VERSION 5.4 ;
NAMESCASESENSITIVE ON ;
BUSBITCHARS "[]" ;
DIVIDERCHAR "/" ;
UNITS
  DATABASE MICRONS 2000 ;
END UNITS
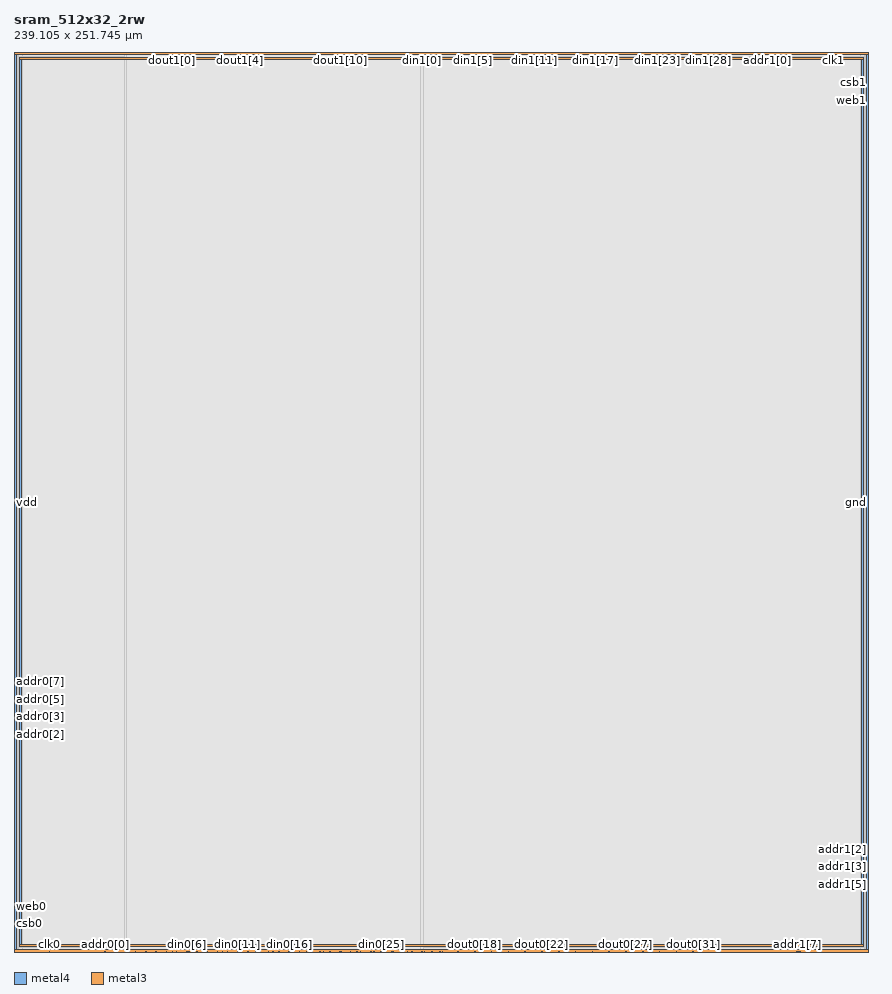
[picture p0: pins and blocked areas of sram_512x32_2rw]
MACRO sram_512x32_2rw
   CLASS BLOCK ;
   SIZE 239.105 BY 251.745 ;
   SYMMETRY X Y R90 ;
   PIN din0[0]
      DIRECTION INPUT ;
      PORT
         LAYER metal4 ;
         RECT  31.1175 0.0 31.2575 0.14 ;
      END
   END din0[0]
   PIN din0[1]
      DIRECTION INPUT ;
      PORT
         LAYER metal4 ;
         RECT  33.9775 0.0 34.1175 0.14 ;
      END
   END din0[1]
   PIN din0[2]
      DIRECTION INPUT ;
      PORT
         LAYER metal4 ;
         RECT  36.8375 0.0 36.9775 0.14 ;
      END
   END din0[2]
   PIN din0[3]
      DIRECTION INPUT ;
      PORT
         LAYER metal4 ;
         RECT  39.6975 0.0 39.8375 0.14 ;
      END
   END din0[3]
   PIN din0[4]
      DIRECTION INPUT ;
      PORT
         LAYER metal4 ;
         RECT  42.5575 0.0 42.6975 0.14 ;
      END
   END din0[4]
   PIN din0[5]
      DIRECTION INPUT ;
      PORT
         LAYER metal4 ;
         RECT  45.4175 0.0 45.5575 0.14 ;
      END
   END din0[5]
   PIN din0[6]
      DIRECTION INPUT ;
      PORT
         LAYER metal4 ;
         RECT  48.2775 0.0 48.4175 0.14 ;
      END
   END din0[6]
   PIN din0[7]
      DIRECTION INPUT ;
      PORT
         LAYER metal4 ;
         RECT  51.1375 0.0 51.2775 0.14 ;
      END
   END din0[7]
   PIN din0[8]
      DIRECTION INPUT ;
      PORT
         LAYER metal4 ;
         RECT  53.9975 0.0 54.1375 0.14 ;
      END
   END din0[8]
   PIN din0[9]
      DIRECTION INPUT ;
      PORT
         LAYER metal4 ;
         RECT  56.8575 0.0 56.9975 0.14 ;
      END
   END din0[9]
   PIN din0[10]
      DIRECTION INPUT ;
      PORT
         LAYER metal4 ;
         RECT  59.7175 0.0 59.8575 0.14 ;
      END
   END din0[10]
   PIN din0[11]
      DIRECTION INPUT ;
      PORT
         LAYER metal4 ;
         RECT  62.5775 0.0 62.7175 0.14 ;
      END
   END din0[11]
   PIN din0[12]
      DIRECTION INPUT ;
      PORT
         LAYER metal4 ;
         RECT  65.4375 0.0 65.5775 0.14 ;
      END
   END din0[12]
   PIN din0[13]
      DIRECTION INPUT ;
      PORT
         LAYER metal4 ;
         RECT  68.2975 0.0 68.4375 0.14 ;
      END
   END din0[13]
   PIN din0[14]
      DIRECTION INPUT ;
      PORT
         LAYER metal4 ;
         RECT  71.1575 0.0 71.2975 0.14 ;
      END
   END din0[14]
   PIN din0[15]
      DIRECTION INPUT ;
      PORT
         LAYER metal4 ;
         RECT  74.0175 0.0 74.1575 0.14 ;
      END
   END din0[15]
   PIN din0[16]
      DIRECTION INPUT ;
      PORT
         LAYER metal4 ;
         RECT  76.8775 0.0 77.0175 0.14 ;
      END
   END din0[16]
   PIN din0[17]
      DIRECTION INPUT ;
      PORT
         LAYER metal4 ;
         RECT  79.7375 0.0 79.8775 0.14 ;
      END
   END din0[17]
   PIN din0[18]
      DIRECTION INPUT ;
      PORT
         LAYER metal4 ;
         RECT  82.5975 0.0 82.7375 0.14 ;
      END
   END din0[18]
   PIN din0[19]
      DIRECTION INPUT ;
      PORT
         LAYER metal4 ;
         RECT  85.4575 0.0 85.5975 0.14 ;
      END
   END din0[19]
   PIN din0[20]
      DIRECTION INPUT ;
      PORT
         LAYER metal4 ;
         RECT  88.3175 0.0 88.4575 0.14 ;
      END
   END din0[20]
   PIN din0[21]
      DIRECTION INPUT ;
      PORT
         LAYER metal4 ;
         RECT  91.1775 0.0 91.3175 0.14 ;
      END
   END din0[21]
   PIN din0[22]
      DIRECTION INPUT ;
      PORT
         LAYER metal4 ;
         RECT  94.0375 0.0 94.1775 0.14 ;
      END
   END din0[22]
   PIN din0[23]
      DIRECTION INPUT ;
      PORT
         LAYER metal4 ;
         RECT  96.8975 0.0 97.0375 0.14 ;
      END
   END din0[23]
   PIN din0[24]
      DIRECTION INPUT ;
      PORT
         LAYER metal4 ;
         RECT  99.7575 0.0 99.8975 0.14 ;
      END
   END din0[24]
   PIN din0[25]
      DIRECTION INPUT ;
      PORT
         LAYER metal4 ;
         RECT  102.6175 0.0 102.7575 0.14 ;
      END
   END din0[25]
   PIN din0[26]
      DIRECTION INPUT ;
      PORT
         LAYER metal4 ;
         RECT  105.4775 0.0 105.6175 0.14 ;
      END
   END din0[26]
   PIN din0[27]
      DIRECTION INPUT ;
      PORT
         LAYER metal4 ;
         RECT  108.3375 0.0 108.4775 0.14 ;
      END
   END din0[27]
   PIN din0[28]
      DIRECTION INPUT ;
      PORT
         LAYER metal4 ;
         RECT  111.1975 0.0 111.3375 0.14 ;
      END
   END din0[28]
   PIN din0[29]
      DIRECTION INPUT ;
      PORT
         LAYER metal4 ;
         RECT  114.0575 0.0 114.1975 0.14 ;
      END
   END din0[29]
   PIN din0[30]
      DIRECTION INPUT ;
      PORT
         LAYER metal4 ;
         RECT  116.9175 0.0 117.0575 0.14 ;
      END
   END din0[30]
   PIN din0[31]
      DIRECTION INPUT ;
      PORT
         LAYER metal4 ;
         RECT  119.7775 0.0 119.9175 0.14 ;
      END
   END din0[31]
   PIN din1[0]
      DIRECTION INPUT ;
      PORT
         LAYER metal4 ;
         RECT  114.0325 251.605 114.1725 251.745 ;
      END
   END din1[0]
   PIN din1[1]
      DIRECTION INPUT ;
      PORT
         LAYER metal4 ;
         RECT  116.8925 251.605 117.0325 251.745 ;
      END
   END din1[1]
   PIN din1[2]
      DIRECTION INPUT ;
      PORT
         LAYER metal4 ;
         RECT  119.7525 251.605 119.8925 251.745 ;
      END
   END din1[2]
   PIN din1[3]
      DIRECTION INPUT ;
      PORT
         LAYER metal4 ;
         RECT  122.6125 251.605 122.7525 251.745 ;
      END
   END din1[3]
   PIN din1[4]
      DIRECTION INPUT ;
      PORT
         LAYER metal4 ;
         RECT  125.4725 251.605 125.6125 251.745 ;
      END
   END din1[4]
   PIN din1[5]
      DIRECTION INPUT ;
      PORT
         LAYER metal4 ;
         RECT  128.3325 251.605 128.4725 251.745 ;
      END
   END din1[5]
   PIN din1[6]
      DIRECTION INPUT ;
      PORT
         LAYER metal4 ;
         RECT  131.1925 251.605 131.3325 251.745 ;
      END
   END din1[6]
   PIN din1[7]
      DIRECTION INPUT ;
      PORT
         LAYER metal4 ;
         RECT  134.0525 251.605 134.1925 251.745 ;
      END
   END din1[7]
   PIN din1[8]
      DIRECTION INPUT ;
      PORT
         LAYER metal4 ;
         RECT  136.9125 251.605 137.0525 251.745 ;
      END
   END din1[8]
   PIN din1[9]
      DIRECTION INPUT ;
      PORT
         LAYER metal4 ;
         RECT  139.7725 251.605 139.9125 251.745 ;
      END
   END din1[9]
   PIN din1[10]
      DIRECTION INPUT ;
      PORT
         LAYER metal4 ;
         RECT  142.6325 251.605 142.7725 251.745 ;
      END
   END din1[10]
   PIN din1[11]
      DIRECTION INPUT ;
      PORT
         LAYER metal4 ;
         RECT  145.4925 251.605 145.6325 251.745 ;
      END
   END din1[11]
   PIN din1[12]
      DIRECTION INPUT ;
      PORT
         LAYER metal4 ;
         RECT  148.3525 251.605 148.4925 251.745 ;
      END
   END din1[12]
   PIN din1[13]
      DIRECTION INPUT ;
      PORT
         LAYER metal4 ;
         RECT  151.2125 251.605 151.3525 251.745 ;
      END
   END din1[13]
   PIN din1[14]
      DIRECTION INPUT ;
      PORT
         LAYER metal4 ;
         RECT  154.0725 251.605 154.2125 251.745 ;
      END
   END din1[14]
   PIN din1[15]
      DIRECTION INPUT ;
      PORT
         LAYER metal4 ;
         RECT  156.9325 251.605 157.0725 251.745 ;
      END
   END din1[15]
   PIN din1[16]
      DIRECTION INPUT ;
      PORT
         LAYER metal4 ;
         RECT  159.7925 251.605 159.9325 251.745 ;
      END
   END din1[16]
   PIN din1[17]
      DIRECTION INPUT ;
      PORT
         LAYER metal4 ;
         RECT  162.6525 251.605 162.7925 251.745 ;
      END
   END din1[17]
   PIN din1[18]
      DIRECTION INPUT ;
      PORT
         LAYER metal4 ;
         RECT  165.5125 251.605 165.6525 251.745 ;
      END
   END din1[18]
   PIN din1[19]
      DIRECTION INPUT ;
      PORT
         LAYER metal4 ;
         RECT  168.3725 251.605 168.5125 251.745 ;
      END
   END din1[19]
   PIN din1[20]
      DIRECTION INPUT ;
      PORT
         LAYER metal4 ;
         RECT  171.2325 251.605 171.3725 251.745 ;
      END
   END din1[20]
   PIN din1[21]
      DIRECTION INPUT ;
      PORT
         LAYER metal4 ;
         RECT  174.0925 251.605 174.2325 251.745 ;
      END
   END din1[21]
   PIN din1[22]
      DIRECTION INPUT ;
      PORT
         LAYER metal4 ;
         RECT  176.9525 251.605 177.0925 251.745 ;
      END
   END din1[22]
   PIN din1[23]
      DIRECTION INPUT ;
      PORT
         LAYER metal4 ;
         RECT  179.8125 251.605 179.9525 251.745 ;
      END
   END din1[23]
   PIN din1[24]
      DIRECTION INPUT ;
      PORT
         LAYER metal4 ;
         RECT  182.6725 251.605 182.8125 251.745 ;
      END
   END din1[24]
   PIN din1[25]
      DIRECTION INPUT ;
      PORT
         LAYER metal4 ;
         RECT  185.5325 251.605 185.6725 251.745 ;
      END
   END din1[25]
   PIN din1[26]
      DIRECTION INPUT ;
      PORT
         LAYER metal4 ;
         RECT  188.3925 251.605 188.5325 251.745 ;
      END
   END din1[26]
   PIN din1[27]
      DIRECTION INPUT ;
      PORT
         LAYER metal4 ;
         RECT  191.2525 251.605 191.3925 251.745 ;
      END
   END din1[27]
   PIN din1[28]
      DIRECTION INPUT ;
      PORT
         LAYER metal4 ;
         RECT  194.1125 251.605 194.2525 251.745 ;
      END
   END din1[28]
   PIN din1[29]
      DIRECTION INPUT ;
      PORT
         LAYER metal4 ;
         RECT  196.9725 251.605 197.1125 251.745 ;
      END
   END din1[29]
   PIN din1[30]
      DIRECTION INPUT ;
      PORT
         LAYER metal4 ;
         RECT  199.8325 251.605 199.9725 251.745 ;
      END
   END din1[30]
   PIN din1[31]
      DIRECTION INPUT ;
      PORT
         LAYER metal4 ;
         RECT  202.6925 251.605 202.8325 251.745 ;
      END
   END din1[31]
   PIN addr0[0]
      DIRECTION INPUT ;
      PORT
         LAYER metal4 ;
         RECT  25.3975 0.0 25.5375 0.14 ;
      END
   END addr0[0]
   PIN addr0[1]
      DIRECTION INPUT ;
      PORT
         LAYER metal4 ;
         RECT  28.2575 0.0 28.3975 0.14 ;
      END
   END addr0[1]
   PIN addr0[2]
      DIRECTION INPUT ;
      PORT
         LAYER metal3 ;
         RECT  0.0 60.84 0.14 60.98 ;
      END
   END addr0[2]
   PIN addr0[3]
      DIRECTION INPUT ;
      PORT
         LAYER metal3 ;
         RECT  0.0 63.57 0.14 63.71 ;
      END
   END addr0[3]
   PIN addr0[4]
      DIRECTION INPUT ;
      PORT
         LAYER metal3 ;
         RECT  0.0 65.78 0.14 65.92 ;
      END
   END addr0[4]
   PIN addr0[5]
      DIRECTION INPUT ;
      PORT
         LAYER metal3 ;
         RECT  0.0 68.51 0.14 68.65 ;
      END
   END addr0[5]
   PIN addr0[6]
      DIRECTION INPUT ;
      PORT
         LAYER metal3 ;
         RECT  0.0 70.72 0.14 70.86 ;
      END
   END addr0[6]
   PIN addr0[7]
      DIRECTION INPUT ;
      PORT
         LAYER metal3 ;
         RECT  0.0 73.45 0.14 73.59 ;
      END
   END addr0[7]
   PIN addr0[8]
      DIRECTION INPUT ;
      PORT
         LAYER metal3 ;
         RECT  0.0 75.66 0.14 75.8 ;
      END
   END addr0[8]
   PIN addr1[0]
      DIRECTION INPUT ;
      PORT
         LAYER metal4 ;
         RECT  210.7075 251.605 210.8475 251.745 ;
      END
   END addr1[0]
   PIN addr1[1]
      DIRECTION INPUT ;
      PORT
         LAYER metal4 ;
         RECT  207.8475 251.605 207.9875 251.745 ;
      END
   END addr1[1]
   PIN addr1[2]
      DIRECTION INPUT ;
      PORT
         LAYER metal3 ;
         RECT  238.965 28.73 239.105 28.87 ;
      END
   END addr1[2]
   PIN addr1[3]
      DIRECTION INPUT ;
      PORT
         LAYER metal3 ;
         RECT  238.965 26.0 239.105 26.14 ;
      END
   END addr1[3]
   PIN addr1[4]
      DIRECTION INPUT ;
      PORT
         LAYER metal3 ;
         RECT  238.965 23.79 239.105 23.93 ;
      END
   END addr1[4]
   PIN addr1[5]
      DIRECTION INPUT ;
      PORT
         LAYER metal3 ;
         RECT  238.965 21.06 239.105 21.2 ;
      END
   END addr1[5]
   PIN addr1[6]
      DIRECTION INPUT ;
      PORT
         LAYER metal4 ;
         RECT  219.855 0.0 219.995 0.14 ;
      END
   END addr1[6]
   PIN addr1[7]
      DIRECTION INPUT ;
      PORT
         LAYER metal4 ;
         RECT  219.0 0.0 219.14 0.14 ;
      END
   END addr1[7]
   PIN addr1[8]
      DIRECTION INPUT ;
      PORT
         LAYER metal4 ;
         RECT  219.285 0.0 219.425 0.14 ;
      END
   END addr1[8]
   PIN csb0
      DIRECTION INPUT ;
      PORT
         LAYER metal3 ;
         RECT  0.0 7.8 0.14 7.94 ;
      END
   END csb0
   PIN csb1
      DIRECTION INPUT ;
      PORT
         LAYER metal3 ;
         RECT  238.965 243.05 239.105 243.19 ;
      END
   END csb1
   PIN web0
      DIRECTION INPUT ;
      PORT
         LAYER metal3 ;
         RECT  0.0 10.53 0.14 10.67 ;
      END
   END web0
   PIN web1
      DIRECTION INPUT ;
      PORT
         LAYER metal3 ;
         RECT  238.965 240.32 239.105 240.46 ;
      END
   END web1
   PIN clk0
      DIRECTION INPUT ;
      PORT
         LAYER metal4 ;
         RECT  9.84 0.0 9.98 0.14 ;
      END
   END clk0
   PIN clk1
      DIRECTION INPUT ;
      PORT
         LAYER metal4 ;
         RECT  229.125 251.605 229.265 251.745 ;
      END
   END clk1
   PIN dout0[0]
      DIRECTION OUTPUT ;
      PORT
         LAYER metal4 ;
         RECT  44.2125 0.0 44.3525 0.14 ;
      END
   END dout0[0]
   PIN dout0[1]
      DIRECTION OUTPUT ;
      PORT
         LAYER metal4 ;
         RECT  48.9125 0.0 49.0525 0.14 ;
      END
   END dout0[1]
   PIN dout0[2]
      DIRECTION OUTPUT ;
      PORT
         LAYER metal4 ;
         RECT  53.24 0.0 53.38 0.14 ;
      END
   END dout0[2]
   PIN dout0[3]
      DIRECTION OUTPUT ;
      PORT
         LAYER metal4 ;
         RECT  58.3125 0.0 58.4525 0.14 ;
      END
   END dout0[3]
   PIN dout0[4]
      DIRECTION OUTPUT ;
      PORT
         LAYER metal4 ;
         RECT  63.0125 0.0 63.1525 0.14 ;
      END
   END dout0[4]
   PIN dout0[5]
      DIRECTION OUTPUT ;
      PORT
         LAYER metal4 ;
         RECT  67.4775 0.0 67.6175 0.14 ;
      END
   END dout0[5]
   PIN dout0[6]
      DIRECTION OUTPUT ;
      PORT
         LAYER metal4 ;
         RECT  72.4125 0.0 72.5525 0.14 ;
      END
   END dout0[6]
   PIN dout0[7]
      DIRECTION OUTPUT ;
      PORT
         LAYER metal4 ;
         RECT  77.1625 0.0 77.3025 0.14 ;
      END
   END dout0[7]
   PIN dout0[8]
      DIRECTION OUTPUT ;
      PORT
         LAYER metal4 ;
         RECT  81.8125 0.0 81.9525 0.14 ;
      END
   END dout0[8]
   PIN dout0[9]
      DIRECTION OUTPUT ;
      PORT
         LAYER metal4 ;
         RECT  86.5125 0.0 86.6525 0.14 ;
      END
   END dout0[9]
   PIN dout0[10]
      DIRECTION OUTPUT ;
      PORT
         LAYER metal4 ;
         RECT  91.4625 0.0 91.6025 0.14 ;
      END
   END dout0[10]
   PIN dout0[11]
      DIRECTION OUTPUT ;
      PORT
         LAYER metal4 ;
         RECT  95.9125 0.0 96.0525 0.14 ;
      END
   END dout0[11]
   PIN dout0[12]
      DIRECTION OUTPUT ;
      PORT
         LAYER metal4 ;
         RECT  100.6125 0.0 100.7525 0.14 ;
      END
   END dout0[12]
   PIN dout0[13]
      DIRECTION OUTPUT ;
      PORT
         LAYER metal4 ;
         RECT  105.885 0.0 106.025 0.14 ;
      END
   END dout0[13]
   PIN dout0[14]
      DIRECTION OUTPUT ;
      PORT
         LAYER metal4 ;
         RECT  110.0125 0.0 110.1525 0.14 ;
      END
   END dout0[14]
   PIN dout0[15]
      DIRECTION OUTPUT ;
      PORT
         LAYER metal4 ;
         RECT  114.7125 0.0 114.8525 0.14 ;
      END
   END dout0[15]
   PIN dout0[16]
      DIRECTION OUTPUT ;
      PORT
         LAYER metal4 ;
         RECT  119.02 0.0 119.16 0.14 ;
      END
   END dout0[16]
   PIN dout0[17]
      DIRECTION OUTPUT ;
      PORT
         LAYER metal4 ;
         RECT  124.1125 0.0 124.2525 0.14 ;
      END
   END dout0[17]
   PIN dout0[18]
      DIRECTION OUTPUT ;
      PORT
         LAYER metal4 ;
         RECT  128.8125 0.0 128.9525 0.14 ;
      END
   END dout0[18]
   PIN dout0[19]
      DIRECTION OUTPUT ;
      PORT
         LAYER metal4 ;
         RECT  133.5125 0.0 133.6525 0.14 ;
      END
   END dout0[19]
   PIN dout0[20]
      DIRECTION OUTPUT ;
      PORT
         LAYER metal4 ;
         RECT  138.2125 0.0 138.3525 0.14 ;
      END
   END dout0[20]
   PIN dout0[21]
      DIRECTION OUTPUT ;
      PORT
         LAYER metal4 ;
         RECT  142.9125 0.0 143.0525 0.14 ;
      END
   END dout0[21]
   PIN dout0[22]
      DIRECTION OUTPUT ;
      PORT
         LAYER metal4 ;
         RECT  147.6125 0.0 147.7525 0.14 ;
      END
   END dout0[22]
   PIN dout0[23]
      DIRECTION OUTPUT ;
      PORT
         LAYER metal4 ;
         RECT  152.3125 0.0 152.4525 0.14 ;
      END
   END dout0[23]
   PIN dout0[24]
      DIRECTION OUTPUT ;
      PORT
         LAYER metal4 ;
         RECT  157.0125 0.0 157.1525 0.14 ;
      END
   END dout0[24]
   PIN dout0[25]
      DIRECTION OUTPUT ;
      PORT
         LAYER metal4 ;
         RECT  161.7125 0.0 161.8525 0.14 ;
      END
   END dout0[25]
   PIN dout0[26]
      DIRECTION OUTPUT ;
      PORT
         LAYER metal4 ;
         RECT  166.4125 0.0 166.5525 0.14 ;
      END
   END dout0[26]
   PIN dout0[27]
      DIRECTION OUTPUT ;
      PORT
         LAYER metal4 ;
         RECT  171.1125 0.0 171.2525 0.14 ;
      END
   END dout0[27]
   PIN dout0[28]
      DIRECTION OUTPUT ;
      PORT
         LAYER metal4 ;
         RECT  175.8125 0.0 175.9525 0.14 ;
      END
   END dout0[28]
   PIN dout0[29]
      DIRECTION OUTPUT ;
      PORT
         LAYER metal4 ;
         RECT  180.5125 0.0 180.6525 0.14 ;
      END
   END dout0[29]
   PIN dout0[30]
      DIRECTION OUTPUT ;
      PORT
         LAYER metal4 ;
         RECT  185.2125 0.0 185.3525 0.14 ;
      END
   END dout0[30]
   PIN dout0[31]
      DIRECTION OUTPUT ;
      PORT
         LAYER metal4 ;
         RECT  189.9125 0.0 190.0525 0.14 ;
      END
   END dout0[31]
   PIN dout1[0]
      DIRECTION OUTPUT ;
      PORT
         LAYER metal4 ;
         RECT  44.2125 251.605 44.3525 251.745 ;
      END
   END dout1[0]
   PIN dout1[1]
      DIRECTION OUTPUT ;
      PORT
         LAYER metal4 ;
         RECT  48.9125 251.605 49.0525 251.745 ;
      END
   END dout1[1]
   PIN dout1[2]
      DIRECTION OUTPUT ;
      PORT
         LAYER metal4 ;
         RECT  53.6125 251.605 53.7525 251.745 ;
      END
   END dout1[2]
   PIN dout1[3]
      DIRECTION OUTPUT ;
      PORT
         LAYER metal4 ;
         RECT  58.3125 251.605 58.4525 251.745 ;
      END
   END dout1[3]
   PIN dout1[4]
      DIRECTION OUTPUT ;
      PORT
         LAYER metal4 ;
         RECT  63.0125 251.605 63.1525 251.745 ;
      END
   END dout1[4]
   PIN dout1[5]
      DIRECTION OUTPUT ;
      PORT
         LAYER metal4 ;
         RECT  67.7125 251.605 67.8525 251.745 ;
      END
   END dout1[5]
   PIN dout1[6]
      DIRECTION OUTPUT ;
      PORT
         LAYER metal4 ;
         RECT  72.4125 251.605 72.5525 251.745 ;
      END
   END dout1[6]
   PIN dout1[7]
      DIRECTION OUTPUT ;
      PORT
         LAYER metal4 ;
         RECT  77.1125 251.605 77.2525 251.745 ;
      END
   END dout1[7]
   PIN dout1[8]
      DIRECTION OUTPUT ;
      PORT
         LAYER metal4 ;
         RECT  81.8125 251.605 81.9525 251.745 ;
      END
   END dout1[8]
   PIN dout1[9]
      DIRECTION OUTPUT ;
      PORT
         LAYER metal4 ;
         RECT  86.5125 251.605 86.6525 251.745 ;
      END
   END dout1[9]
   PIN dout1[10]
      DIRECTION OUTPUT ;
      PORT
         LAYER metal4 ;
         RECT  91.2125 251.605 91.3525 251.745 ;
      END
   END dout1[10]
   PIN dout1[11]
      DIRECTION OUTPUT ;
      PORT
         LAYER metal4 ;
         RECT  95.9125 251.605 96.0525 251.745 ;
      END
   END dout1[11]
   PIN dout1[12]
      DIRECTION OUTPUT ;
      PORT
         LAYER metal4 ;
         RECT  100.6125 251.605 100.7525 251.745 ;
      END
   END dout1[12]
   PIN dout1[13]
      DIRECTION OUTPUT ;
      PORT
         LAYER metal4 ;
         RECT  105.3125 251.605 105.4525 251.745 ;
      END
   END dout1[13]
   PIN dout1[14]
      DIRECTION OUTPUT ;
      PORT
         LAYER metal4 ;
         RECT  110.0125 251.605 110.1525 251.745 ;
      END
   END dout1[14]
   PIN dout1[15]
      DIRECTION OUTPUT ;
      PORT
         LAYER metal4 ;
         RECT  114.7125 251.605 114.8525 251.745 ;
      END
   END dout1[15]
   PIN dout1[16]
      DIRECTION OUTPUT ;
      PORT
         LAYER metal4 ;
         RECT  118.995 251.605 119.135 251.745 ;
      END
   END dout1[16]
   PIN dout1[17]
      DIRECTION OUTPUT ;
      PORT
         LAYER metal4 ;
         RECT  124.1125 251.605 124.2525 251.745 ;
      END
   END dout1[17]
   PIN dout1[18]
      DIRECTION OUTPUT ;
      PORT
         LAYER metal4 ;
         RECT  128.8125 251.605 128.9525 251.745 ;
      END
   END dout1[18]
   PIN dout1[19]
      DIRECTION OUTPUT ;
      PORT
         LAYER metal4 ;
         RECT  133.2775 251.605 133.4175 251.745 ;
      END
   END dout1[19]
   PIN dout1[20]
      DIRECTION OUTPUT ;
      PORT
         LAYER metal4 ;
         RECT  138.2125 251.605 138.3525 251.745 ;
      END
   END dout1[20]
   PIN dout1[21]
      DIRECTION OUTPUT ;
      PORT
         LAYER metal4 ;
         RECT  142.9175 251.605 143.0575 251.745 ;
      END
   END dout1[21]
   PIN dout1[22]
      DIRECTION OUTPUT ;
      PORT
         LAYER metal4 ;
         RECT  147.595 251.605 147.735 251.745 ;
      END
   END dout1[22]
   PIN dout1[23]
      DIRECTION OUTPUT ;
      PORT
         LAYER metal4 ;
         RECT  152.3125 251.605 152.4525 251.745 ;
      END
   END dout1[23]
   PIN dout1[24]
      DIRECTION OUTPUT ;
      PORT
         LAYER metal4 ;
         RECT  157.2175 251.605 157.3575 251.745 ;
      END
   END dout1[24]
   PIN dout1[25]
      DIRECTION OUTPUT ;
      PORT
         LAYER metal4 ;
         RECT  161.7125 251.605 161.8525 251.745 ;
      END
   END dout1[25]
   PIN dout1[26]
      DIRECTION OUTPUT ;
      PORT
         LAYER metal4 ;
         RECT  166.4125 251.605 166.5525 251.745 ;
      END
   END dout1[26]
   PIN dout1[27]
      DIRECTION OUTPUT ;
      PORT
         LAYER metal4 ;
         RECT  171.685 251.605 171.825 251.745 ;
      END
   END dout1[27]
   PIN dout1[28]
      DIRECTION OUTPUT ;
      PORT
         LAYER metal4 ;
         RECT  175.8125 251.605 175.9525 251.745 ;
      END
   END dout1[28]
   PIN dout1[29]
      DIRECTION OUTPUT ;
      PORT
         LAYER metal4 ;
         RECT  180.5125 251.605 180.6525 251.745 ;
      END
   END dout1[29]
   PIN dout1[30]
      DIRECTION OUTPUT ;
      PORT
         LAYER metal4 ;
         RECT  184.775 251.605 184.915 251.745 ;
      END
   END dout1[30]
   PIN dout1[31]
      DIRECTION OUTPUT ;
      PORT
         LAYER metal4 ;
         RECT  189.9125 251.605 190.0525 251.745 ;
      END
   END dout1[31]
   PIN vdd
      DIRECTION INOUT ;
      USE POWER ; 
      SHAPE ABUTMENT ; 
      PORT
         LAYER metal4 ;
         RECT  238.405 0.0 239.105 251.745 ;
         LAYER metal3 ;
         RECT  0.0 251.045 239.105 251.745 ;
         LAYER metal4 ;
         RECT  0.0 0.0 0.7 251.745 ;
         LAYER metal3 ;
         RECT  0.0 0.0 239.105 0.7 ;
      END
   END vdd
   PIN gnd
      DIRECTION INOUT ;
      USE GROUND ; 
      SHAPE ABUTMENT ; 
      PORT
         LAYER metal3 ;
         RECT  1.4 249.645 237.705 250.345 ;
         LAYER metal3 ;
         RECT  1.4 1.4 237.705 2.1 ;
         LAYER metal4 ;
         RECT  237.005 1.4 237.705 250.345 ;
         LAYER metal4 ;
         RECT  1.4 1.4 2.1 250.345 ;
      END
   END gnd
   OBS
   LAYER  metal1 ;
      RECT  0.14 0.14 238.965 251.605 ;
   LAYER  metal2 ;
      RECT  0.14 0.14 238.965 251.605 ;
   LAYER  metal3 ;
      RECT  0.28 60.7 238.965 61.12 ;
      RECT  0.14 61.12 0.28 63.43 ;
      RECT  0.14 63.85 0.28 65.64 ;
      RECT  0.14 66.06 0.28 68.37 ;
      RECT  0.14 68.79 0.28 70.58 ;
      RECT  0.14 71.0 0.28 73.31 ;
      RECT  0.14 73.73 0.28 75.52 ;
      RECT  0.28 28.59 238.825 29.01 ;
      RECT  0.28 29.01 238.825 60.7 ;
      RECT  238.825 29.01 238.965 60.7 ;
      RECT  238.825 26.28 238.965 28.59 ;
      RECT  238.825 24.07 238.965 25.86 ;
      RECT  238.825 21.34 238.965 23.65 ;
      RECT  0.28 61.12 238.825 242.91 ;
      RECT  0.28 242.91 238.825 243.33 ;
      RECT  0.14 8.08 0.28 10.39 ;
      RECT  0.14 10.81 0.28 60.7 ;
      RECT  238.825 61.12 238.965 240.18 ;
      RECT  238.825 240.6 238.965 242.91 ;
      RECT  0.14 75.94 0.28 250.905 ;
      RECT  238.825 243.33 238.965 250.905 ;
      RECT  238.825 0.84 238.965 20.92 ;
      RECT  0.14 0.84 0.28 7.66 ;
      RECT  0.28 243.33 1.26 249.505 ;
      RECT  0.28 249.505 1.26 250.485 ;
      RECT  0.28 250.485 1.26 250.905 ;
      RECT  1.26 243.33 237.845 249.505 ;
      RECT  1.26 250.485 237.845 250.905 ;
      RECT  237.845 243.33 238.825 249.505 ;
      RECT  237.845 249.505 238.825 250.485 ;
      RECT  237.845 250.485 238.825 250.905 ;
      RECT  0.28 0.84 1.26 1.26 ;
      RECT  0.28 1.26 1.26 2.24 ;
      RECT  0.28 2.24 1.26 28.59 ;
      RECT  1.26 0.84 237.845 1.26 ;
      RECT  1.26 2.24 237.845 28.59 ;
      RECT  237.845 0.84 238.825 1.26 ;
      RECT  237.845 1.26 238.825 2.24 ;
      RECT  237.845 2.24 238.825 28.59 ;
   LAYER  metal4 ;
      RECT  30.8375 0.42 31.5375 251.605 ;
      RECT  31.5375 0.14 33.6975 0.42 ;
      RECT  34.3975 0.14 36.5575 0.42 ;
      RECT  37.2575 0.14 39.4175 0.42 ;
      RECT  40.1175 0.14 42.2775 0.42 ;
      RECT  45.8375 0.14 47.9975 0.42 ;
      RECT  54.4175 0.14 56.5775 0.42 ;
      RECT  60.1375 0.14 62.2975 0.42 ;
      RECT  68.7175 0.14 70.8775 0.42 ;
      RECT  74.4375 0.14 76.5975 0.42 ;
      RECT  83.0175 0.14 85.1775 0.42 ;
      RECT  88.7375 0.14 90.8975 0.42 ;
      RECT  97.3175 0.14 99.4775 0.42 ;
      RECT  103.0375 0.14 105.1975 0.42 ;
      RECT  111.6175 0.14 113.7775 0.42 ;
      RECT  31.5375 0.42 113.7525 251.325 ;
      RECT  113.7525 0.42 114.4525 251.325 ;
      RECT  120.1725 251.325 122.3325 251.605 ;
      RECT  125.8925 251.325 128.0525 251.605 ;
      RECT  134.4725 251.325 136.6325 251.605 ;
      RECT  140.1925 251.325 142.3525 251.605 ;
      RECT  148.7725 251.325 150.9325 251.605 ;
      RECT  154.4925 251.325 156.6525 251.605 ;
      RECT  163.0725 251.325 165.2325 251.605 ;
      RECT  168.7925 251.325 170.9525 251.605 ;
      RECT  177.3725 251.325 179.5325 251.605 ;
      RECT  185.9525 251.325 188.1125 251.605 ;
      RECT  191.6725 251.325 193.8325 251.605 ;
      RECT  194.5325 251.325 196.6925 251.605 ;
      RECT  197.3925 251.325 199.5525 251.605 ;
      RECT  200.2525 251.325 202.4125 251.605 ;
      RECT  25.8175 0.14 27.9775 0.42 ;
      RECT  28.6775 0.14 30.8375 0.42 ;
      RECT  203.1125 251.325 207.5675 251.605 ;
      RECT  208.2675 251.325 210.4275 251.605 ;
      RECT  10.26 0.14 25.1175 0.42 ;
      RECT  211.1275 251.325 228.845 251.605 ;
      RECT  42.9775 0.14 43.9325 0.42 ;
      RECT  44.6325 0.14 45.1375 0.42 ;
      RECT  49.3325 0.14 50.8575 0.42 ;
      RECT  51.5575 0.14 52.96 0.42 ;
      RECT  53.66 0.14 53.7175 0.42 ;
      RECT  57.2775 0.14 58.0325 0.42 ;
      RECT  58.7325 0.14 59.4375 0.42 ;
      RECT  63.4325 0.14 65.1575 0.42 ;
      RECT  65.8575 0.14 67.1975 0.42 ;
      RECT  67.8975 0.14 68.0175 0.42 ;
      RECT  71.5775 0.14 72.1325 0.42 ;
      RECT  72.8325 0.14 73.7375 0.42 ;
      RECT  77.5825 0.14 79.4575 0.42 ;
      RECT  80.1575 0.14 81.5325 0.42 ;
      RECT  82.2325 0.14 82.3175 0.42 ;
      RECT  85.8775 0.14 86.2325 0.42 ;
      RECT  86.9325 0.14 88.0375 0.42 ;
      RECT  91.8825 0.14 93.7575 0.42 ;
      RECT  94.4575 0.14 95.6325 0.42 ;
      RECT  96.3325 0.14 96.6175 0.42 ;
      RECT  100.1775 0.14 100.3325 0.42 ;
      RECT  101.0325 0.14 102.3375 0.42 ;
      RECT  106.305 0.14 108.0575 0.42 ;
      RECT  108.7575 0.14 109.7325 0.42 ;
      RECT  110.4325 0.14 110.9175 0.42 ;
      RECT  115.1325 0.14 116.6375 0.42 ;
      RECT  117.3375 0.14 118.74 0.42 ;
      RECT  119.44 0.14 119.4975 0.42 ;
      RECT  120.1975 0.14 123.8325 0.42 ;
      RECT  124.5325 0.14 128.5325 0.42 ;
      RECT  129.2325 0.14 133.2325 0.42 ;
      RECT  133.9325 0.14 137.9325 0.42 ;
      RECT  138.6325 0.14 142.6325 0.42 ;
      RECT  143.3325 0.14 147.3325 0.42 ;
      RECT  148.0325 0.14 152.0325 0.42 ;
      RECT  152.7325 0.14 156.7325 0.42 ;
      RECT  157.4325 0.14 161.4325 0.42 ;
      RECT  162.1325 0.14 166.1325 0.42 ;
      RECT  166.8325 0.14 170.8325 0.42 ;
      RECT  171.5325 0.14 175.5325 0.42 ;
      RECT  176.2325 0.14 180.2325 0.42 ;
      RECT  180.9325 0.14 184.9325 0.42 ;
      RECT  185.6325 0.14 189.6325 0.42 ;
      RECT  190.3325 0.14 218.72 0.42 ;
      RECT  31.5375 251.325 43.9325 251.605 ;
      RECT  44.6325 251.325 48.6325 251.605 ;
      RECT  49.3325 251.325 53.3325 251.605 ;
      RECT  54.0325 251.325 58.0325 251.605 ;
      RECT  58.7325 251.325 62.7325 251.605 ;
      RECT  63.4325 251.325 67.4325 251.605 ;
      RECT  68.1325 251.325 72.1325 251.605 ;
      RECT  72.8325 251.325 76.8325 251.605 ;
      RECT  77.5325 251.325 81.5325 251.605 ;
      RECT  82.2325 251.325 86.2325 251.605 ;
      RECT  86.9325 251.325 90.9325 251.605 ;
      RECT  91.6325 251.325 95.6325 251.605 ;
      RECT  96.3325 251.325 100.3325 251.605 ;
      RECT  101.0325 251.325 105.0325 251.605 ;
      RECT  105.7325 251.325 109.7325 251.605 ;
      RECT  110.4325 251.325 113.7525 251.605 ;
      RECT  115.1325 251.325 116.6125 251.605 ;
      RECT  117.3125 251.325 118.715 251.605 ;
      RECT  119.415 251.325 119.4725 251.605 ;
      RECT  123.0325 251.325 123.8325 251.605 ;
      RECT  124.5325 251.325 125.1925 251.605 ;
      RECT  129.2325 251.325 130.9125 251.605 ;
      RECT  131.6125 251.325 132.9975 251.605 ;
      RECT  133.6975 251.325 133.7725 251.605 ;
      RECT  137.3325 251.325 137.9325 251.605 ;
      RECT  138.6325 251.325 139.4925 251.605 ;
      RECT  143.3375 251.325 145.2125 251.605 ;
      RECT  145.9125 251.325 147.315 251.605 ;
      RECT  148.015 251.325 148.0725 251.605 ;
      RECT  151.6325 251.325 152.0325 251.605 ;
      RECT  152.7325 251.325 153.7925 251.605 ;
      RECT  157.6375 251.325 159.5125 251.605 ;
      RECT  160.2125 251.325 161.4325 251.605 ;
      RECT  162.1325 251.325 162.3725 251.605 ;
      RECT  165.9325 251.325 166.1325 251.605 ;
      RECT  166.8325 251.325 168.0925 251.605 ;
      RECT  172.105 251.325 173.8125 251.605 ;
      RECT  174.5125 251.325 175.5325 251.605 ;
      RECT  176.2325 251.325 176.6725 251.605 ;
      RECT  180.9325 251.325 182.3925 251.605 ;
      RECT  183.0925 251.325 184.495 251.605 ;
      RECT  185.195 251.325 185.2525 251.605 ;
      RECT  188.8125 251.325 189.6325 251.605 ;
      RECT  190.3325 251.325 190.9725 251.605 ;
      RECT  220.275 0.14 238.125 0.42 ;
      RECT  229.545 251.325 238.125 251.605 ;
      RECT  0.98 0.14 9.56 0.42 ;
      RECT  114.4525 0.42 236.725 1.12 ;
      RECT  114.4525 1.12 236.725 250.625 ;
      RECT  114.4525 250.625 236.725 251.325 ;
      RECT  236.725 0.42 237.985 1.12 ;
      RECT  236.725 250.625 237.985 251.325 ;
      RECT  237.985 0.42 238.125 1.12 ;
      RECT  237.985 1.12 238.125 250.625 ;
      RECT  237.985 250.625 238.125 251.325 ;
      RECT  0.98 0.42 1.12 1.12 ;
      RECT  0.98 1.12 1.12 250.625 ;
      RECT  0.98 250.625 1.12 251.605 ;
      RECT  1.12 0.42 2.38 1.12 ;
      RECT  1.12 250.625 2.38 251.605 ;
      RECT  2.38 0.42 30.8375 1.12 ;
      RECT  2.38 1.12 30.8375 250.625 ;
      RECT  2.38 250.625 30.8375 251.605 ;
   END
END    sram_512x32_2rw
END    LIBRARY
